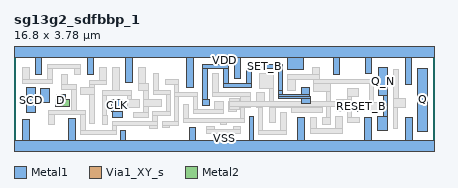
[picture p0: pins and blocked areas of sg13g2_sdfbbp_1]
MACRO sg13g2_sdfbbp_1
  CLASS CORE ;
  FOREIGN sg13g2_sdfbbp_1 ;
  ORIGIN 0.000 0.000 ;
  SIZE 16.800 BY 3.780 ;
  SYMMETRY X Y ;
  SITE CoreSite ;
  PIN Q
    DIRECTION OUTPUT ;
    USE SIGNAL ;
    PORT
      LAYER Metal1 ;
        RECT 16.145 0.590 16.535 3.120 ;
    END
  END Q
  PIN Q_N
    DIRECTION OUTPUT ;
    USE SIGNAL ;
    PORT
      LAYER Metal1 ;
        RECT 14.590 2.005 14.950 3.135 ;
        RECT 14.780 1.190 14.950 2.005 ;
        RECT 14.520 0.610 14.950 1.190 ;
    END
  END Q_N
  PIN RESET_B
    DIRECTION INPUT ;
    USE SIGNAL ;
    PORT
      LAYER Metal1 ;
        RECT 13.740 1.380 14.035 1.790 ;
    END
  END RESET_B
  PIN SET_B
    DIRECTION INPUT ;
    USE SIGNAL ;
    PORT
      LAYER Metal1 ;
        RECT 7.550 3.105 8.560 3.275 ;
        RECT 7.550 1.855 7.720 3.105 ;
        RECT 8.390 2.510 8.560 3.105 ;
        RECT 9.310 3.105 10.740 3.275 ;
        RECT 9.310 2.510 9.480 3.105 ;
        RECT 8.390 2.345 9.480 2.510 ;
        RECT 10.565 2.215 10.740 3.105 ;
        RECT 10.580 2.050 10.740 2.215 ;
        RECT 11.510 2.050 11.810 2.350 ;
        RECT 10.580 2.000 11.810 2.050 ;
        RECT 10.580 1.890 11.840 2.000 ;
        RECT 7.525 1.635 7.815 1.855 ;
        RECT 11.510 1.720 11.840 1.890 ;
    END
  END SET_B
  PIN D
    DIRECTION INPUT ;
    USE SIGNAL ;
    PORT
      LAYER Metal1 ;
        RECT 1.680 1.620 2.050 2.055 ;
      LAYER Via1_XY_s ;
        RECT 1.790 1.645 1.980 1.835 ;
      LAYER Metal2 ;
        RECT 1.645 1.580 2.205 1.860 ;
    END
  END D
  PIN SCE
    DIRECTION INPUT ;
    USE SIGNAL ;
    PORT
      LAYER Metal1 ;
        RECT 1.050 1.750 1.435 2.295 ;
    END
  END SCE
  PIN SCD
    DIRECTION INPUT ;
    USE SIGNAL ;
    PORT
      LAYER Metal1 ;
        RECT 0.510 1.355 0.840 2.325 ;
    END
  END SCD
  PIN CLK
    DIRECTION INPUT ;
    USE SIGNAL ;
    PORT
      LAYER Metal1 ;
        RECT 3.885 1.380 4.340 1.850 ;
        RECT 3.920 1.155 4.340 1.380 ;
    END
  END CLK
  PIN VDD
    DIRECTION INPUT ;
    USE POWER ;
    SHAPE ABUTMENT ;
    PORT
      LAYER Metal1 ;
        RECT 0.000 3.560 16.800 4.000 ;
        RECT 0.850 2.880 1.110 3.560 ;
        RECT 2.920 2.880 3.180 3.560 ;
        RECT 4.460 2.560 4.720 3.560 ;
        RECT 6.915 2.340 7.175 3.560 ;
        RECT 8.815 2.695 9.075 3.560 ;
        RECT 10.925 3.055 11.570 3.560 ;
        RECT 12.765 2.880 13.025 3.560 ;
        RECT 14.055 2.885 14.315 3.560 ;
        RECT 15.645 2.455 15.905 3.560 ;
    END
  END VDD
  PIN VSS
    DIRECTION INPUT ;
    USE GROUND ;
    SHAPE ABUTMENT ;
    PORT
      LAYER Metal1 ;
        RECT 0.340 0.220 0.600 1.055 ;
        RECT 2.185 0.220 2.445 1.095 ;
        RECT 4.260 0.220 4.460 0.635 ;
        RECT 7.010 0.220 7.270 0.745 ;
        RECT 9.415 0.220 9.590 1.175 ;
        RECT 11.340 0.220 11.600 1.160 ;
        RECT 14.035 0.220 14.295 1.140 ;
        RECT 15.675 0.220 15.935 1.155 ;
        RECT 0.000 -0.220 16.800 0.220 ;
    END
  END VSS
  OBS
      LAYER Metal1 ;
        RECT 0.340 2.675 0.600 3.140 ;
        RECT 1.355 3.105 2.660 3.275 ;
        RECT 1.355 2.675 1.555 3.105 ;
        RECT 2.400 2.880 2.660 3.105 ;
        RECT 0.340 2.505 1.555 2.675 ;
        RECT 1.880 2.455 2.140 2.845 ;
        RECT 3.430 2.640 3.690 3.140 ;
        RECT 3.030 2.470 3.690 2.640 ;
        RECT 1.880 2.255 2.495 2.455 ;
        RECT 3.030 2.325 3.215 2.470 ;
        RECT 2.290 1.440 2.495 2.255 ;
        RECT 2.675 2.065 3.215 2.325 ;
        RECT 3.950 2.210 4.210 3.160 ;
        RECT 4.985 2.490 5.245 3.160 ;
        RECT 4.985 2.220 5.360 2.490 ;
        RECT 1.360 1.280 2.850 1.440 ;
        RECT 1.360 0.875 1.620 1.280 ;
        RECT 2.670 0.625 2.850 1.280 ;
        RECT 3.030 0.885 3.215 2.065 ;
        RECT 3.535 2.040 4.700 2.210 ;
        RECT 3.535 1.210 3.695 2.040 ;
        RECT 4.530 1.870 4.700 2.040 ;
        RECT 5.190 1.880 5.360 2.220 ;
        RECT 5.585 2.235 5.785 2.920 ;
        RECT 6.065 2.465 6.580 2.670 ;
        RECT 5.585 2.075 6.240 2.235 ;
        RECT 4.530 1.540 5.005 1.870 ;
        RECT 5.190 1.580 5.900 1.880 ;
        RECT 5.190 1.335 5.360 1.580 ;
        RECT 6.080 1.385 6.240 2.075 ;
        RECT 3.535 0.870 3.740 1.210 ;
        RECT 4.770 1.155 5.360 1.335 ;
        RECT 5.540 1.225 6.240 1.385 ;
        RECT 6.420 2.160 6.580 2.465 ;
        RECT 7.925 2.160 8.160 2.905 ;
        RECT 9.830 2.310 10.380 2.895 ;
        RECT 11.930 2.870 12.205 3.145 ;
        RECT 6.420 1.995 7.330 2.160 ;
        RECT 7.925 2.000 9.470 2.160 ;
        RECT 5.540 0.975 5.730 1.225 ;
        RECT 6.420 0.985 6.580 1.995 ;
        RECT 3.920 0.815 5.730 0.975 ;
        RECT 3.920 0.625 4.080 0.815 ;
        RECT 5.425 0.700 5.730 0.815 ;
        RECT 5.955 0.825 6.580 0.985 ;
        RECT 6.770 1.115 6.975 1.650 ;
        RECT 7.160 1.455 7.330 1.995 ;
        RECT 8.040 1.455 8.370 1.785 ;
        RECT 7.160 1.295 8.370 1.455 ;
        RECT 8.580 1.380 8.885 1.785 ;
        RECT 9.075 1.535 9.470 2.000 ;
        RECT 9.710 1.755 10.030 2.125 ;
        RECT 9.710 1.535 9.930 1.755 ;
        RECT 9.075 1.115 9.235 1.535 ;
        RECT 6.770 0.955 9.235 1.115 ;
        RECT 8.255 0.870 8.515 0.955 ;
        RECT 5.955 0.725 6.220 0.825 ;
        RECT 2.670 0.455 4.080 0.625 ;
        RECT 7.710 0.680 8.005 0.775 ;
        RECT 8.795 0.680 9.055 0.775 ;
        RECT 7.710 0.520 9.055 0.680 ;
        RECT 9.770 0.615 9.930 1.535 ;
        RECT 10.210 1.710 10.380 2.310 ;
        RECT 10.920 2.660 12.205 2.870 ;
        RECT 10.920 2.230 11.250 2.660 ;
        RECT 11.990 2.645 12.205 2.660 ;
        RECT 11.990 2.485 14.375 2.645 ;
        RECT 11.990 2.195 12.670 2.485 ;
        RECT 10.210 1.550 11.250 1.710 ;
        RECT 10.210 0.935 10.440 1.550 ;
        RECT 11.085 1.525 11.250 1.550 ;
        RECT 12.050 1.525 12.330 1.750 ;
        RECT 10.645 0.615 10.905 1.360 ;
        RECT 11.085 1.345 12.330 1.525 ;
        RECT 9.770 0.455 10.905 0.615 ;
        RECT 11.850 0.695 12.110 1.155 ;
        RECT 12.510 1.125 12.670 2.195 ;
        RECT 13.340 1.975 13.795 2.305 ;
        RECT 13.340 1.865 13.500 1.975 ;
        RECT 12.900 1.380 13.500 1.865 ;
        RECT 14.215 1.750 14.375 2.485 ;
        RECT 15.170 1.885 15.375 3.070 ;
        RECT 14.215 1.420 14.550 1.750 ;
        RECT 15.170 1.555 15.645 1.885 ;
        RECT 12.340 0.875 12.670 1.125 ;
        RECT 12.870 0.695 13.130 1.170 ;
        RECT 13.340 1.140 13.500 1.380 ;
        RECT 13.340 0.930 13.815 1.140 ;
        RECT 15.170 0.705 15.355 1.555 ;
        RECT 11.850 0.515 13.130 0.695 ;
      LAYER Metal2 ;
        RECT 8.635 1.780 9.000 1.900 ;
        RECT 13.030 1.780 13.320 1.865 ;
        RECT 8.635 1.580 13.320 1.780 ;
        RECT 8.635 1.455 9.000 1.580 ;
        RECT 13.030 1.470 13.320 1.580 ;
  END
  PROPERTY CatenaDesignType "deviceLevel" ;
END sg13g2_sdfbbp_1
